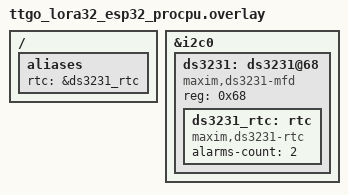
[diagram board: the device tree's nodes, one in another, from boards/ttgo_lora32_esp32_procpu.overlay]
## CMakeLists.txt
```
# SPDX-FileCopyrightText: 2026 Henrique Freire <hfreire10@hotmail.com>

# SPDX-License-Identifier: MIT

cmake_minimum_required(VERSION 3.20.0)

list(APPEND EXTRA_ZEPHYR_MODULES ${CMAKE_CURRENT_LIST_DIR}/../../modules/wifi_sensing)

find_package(Zephyr REQUIRED HINTS $ENV{ZEPHYR_BASE})
project(relay)

target_sources(app PRIVATE
  src/lora.c
  src/main.c
  src/storage.c
  src/time.c
  src/wifi.c
)
target_include_directories(app PRIVATE include)
```

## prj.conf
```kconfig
# SPDX-FileCopyrightText: 2026 Henrique Freire <hfreire10@hotmail.com>

# SPDX-License-Identifier: MIT

# Debug
CONFIG_LOG=y
CONFIG_THREAD_NAME=y
CONFIG_STACK_CANARIES=y
CONFIG_STACK_SENTINEL=y

# General
CONFIG_SPI=y
CONFIG_GPIO=y
CONFIG_FLASH=y
CONFIG_EVENTS=y
CONFIG_FLASH_MAP=y
CONFIG_STREAM_FLASH=y
CONFIG_LOG_DEFAULT_LEVEL=3
CONFIG_IDLE_STACK_SIZE=256
CONFIG_MAIN_STACK_SIZE=2048
CONFIG_HEAP_MEM_POOL_SIZE=102400
CONFIG_SYSTEM_WORKQUEUE_STACK_SIZE=1548

# RTC
CONFIG_I2C=y
CONFIG_RTC=y

# Bootloader
# CONFIG_IMG_MANAGER=y
# CONFIG_MCUBOOT_IMG_MANAGER=y

# Networking
CONFIG_NET_UDP=y
CONFIG_NET_IPV4=y
CONFIG_POSIX_API=y
CONFIG_NETWORKING=y
CONFIG_NET_SOCKETS=y
CONFIG_NET_TX_STACK_SIZE=4096
CONFIG_NET_RX_STACK_SIZE=4096
CONFIG_NET_SOCKETS_SERVICE_STACK_SIZE=3596

## LoRa
CONFIG_LORA=y

## DHCP
CONFIG_NET_DHCPV4_SERVER=y
CONFIG_NET_DHCPV4_SERVER_ADDR_COUNT=8
CONFIG_NET_CONFIG_SETTINGS=y
CONFIG_NET_CONFIG_AUTO_INIT=y
CONFIG_NET_CONFIG_MY_IPV4_GW="192.168.5.1"
CONFIG_NET_CONFIG_MY_IPV4_ADDR="192.168.5.1"
CONFIG_NET_CONFIG_MY_IPV4_NETMASK="255.255.255.0"

## WiFi
CONFIG_WIFI=y
CONFIG_WIFI_ESP32=y
CONFIG_NET_L2_WIFI_MGMT=y
CONFIG_ESP32_WIFI_IRAM_OPT=y
CONFIG_ESP32_WIFI_RX_IRAM_OPT=y
CONFIG_ESP32_WIFI_DYNAMIC_RX_BUFFER_NUM=48
#default value in seconds
CONFIG_WIFI_MGMT_AP_STA_INACTIVITY_TIMEOUT=300

# SD Card
CONFIG_DISK_ACCESS=y
CONFIG_FILE_SYSTEM=y
CONFIG_FS_FATFS_LFN=y
CONFIG_FAT_FILESYSTEM_ELM=y
```

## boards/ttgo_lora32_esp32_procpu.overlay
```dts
&i2c0 {
    status = "okay";

    ds3231: ds3231@68 {
        compatible = "maxim,ds3231-mfd";
        reg = <0x68>;
        status = "okay";

        ds3231_rtc: rtc {
            compatible = "maxim,ds3231-rtc";
            alarms-count = <2>;
            status = "okay";
        };
    };
};

/ {
    aliases {
        rtc = &ds3231_rtc;
    };
};
```

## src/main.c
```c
// SPDX-FileCopyrightText: 2026 Henrique Freire <hfreire10@hotmail.com>

// SPDX-License-Identifier: MIT

#include <zephyr/device.h>
#include <zephyr/kernel.h>
#include <zephyr/logging/log.h>
#include <zephyr/net/wifi_mgmt.h>

#include "lora.h"

#include "relay.h"

#define NET_EVENTS                                                                                 \
  (NET_EVENT_WIFI_AP_ENABLE_RESULT | NET_EVENT_WIFI_AP_STA_CONNECTED |                             \
   NET_EVENT_WIFI_AP_STA_DISCONNECTED)

LOG_MODULE_REGISTER(relay);

const struct device *g_lora_dev = DEVICE_DT_GET(LORA_NODE);

static struct net_mgmt_event_callback s_net_cb;

K_EVENT_DEFINE(g_ap_events);

K_FIFO_DEFINE(g_lora_fifo);
K_FIFO_DEFINE(g_storage_fifo);
K_MEM_SLAB_DEFINE_TYPE(g_csi_slab, csi_item_t, (MAX_MSGS / MAX_MSG_PAYLOAD));

static void net_event_handler(struct net_mgmt_event_callback *cb, uint64_t mgmt_event,
                              struct net_if *iface) {
  switch (mgmt_event) {
  case NET_EVENT_WIFI_AP_ENABLE_RESULT: {
    k_event_post(&g_ap_events, NET_READY);
    LOG_INF("AP Mode is enabled. Waiting for station to connect");
    break;
  }
  case NET_EVENT_WIFI_AP_STA_CONNECTED: {
    LOG_INF("Station connected");
    break;
  }
  case NET_EVENT_WIFI_AP_STA_DISCONNECTED: {
    LOG_INF("Station disconnected");
    break;
  }
  }
}

int main(void) {
  LOG_INF("Starting LoRa <-> Wi-Fi gateway");

  rtc_sync();

  net_mgmt_init_event_callback(&s_net_cb, net_event_handler, NET_EVENTS);
  net_mgmt_add_event_callback(&s_net_cb);

  sd_card_init();
  ap_init();
  lora_init(g_lora_dev, true);

  return 0;
}
```

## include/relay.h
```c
// SPDX-FileCopyrightText: 2026 Henrique Freire <hfreire10@hotmail.com>
//
// SPDX-License-Identifier: MIT

#pragma once

#include <inttypes.h>

#include <zephyr/kernel.h>
#include <zephyr/sys/atomic.h>

#include <wifi_sensing.h>

#define LORA_NODE DT_ALIAS(lora0)

typedef struct {
  void *fifo_reserved;
  atomic_t refs;
  uint8_t data[MSG_HDR_SIZE + MAX_MSG_PAYLOAD * CSI_DATA_SIZE];
} csi_item_t;

extern const struct device *g_lora_dev;
extern const struct device *g_rtc_dev;

extern struct k_event g_ap_events;
extern struct k_fifo g_lora_fifo;
extern struct k_fifo g_storage_fifo;
extern struct k_mem_slab g_csi_slab;

void ap_init(void);
void sd_card_init(void);
int rtc_sync(void);
uint64_t get_timestamp();
int get_current_utc(char *buf, size_t buf_size);
```

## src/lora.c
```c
// SPDX-FileCopyrightText: 2026 Henrique Freire <hfreire10@hotmail.com>

// SPDX-License-Identifier: MIT

#include <inttypes.h>

#include <zephyr/drivers/lora.h>
#include <zephyr/kernel.h>
#include <zephyr/logging/log.h>

#include <lora.h>
#include <wifi_sensing.h>

#include "relay.h"

#define LORA_TX_PRIORITY   4
#define LORA_TX_STACK_SIZE 1024

BUILD_ASSERT(DT_NODE_HAS_STATUS_OKAY(LORA_NODE), "No default LoRa radio specified in DT");

LOG_MODULE_DECLARE(relay);

static void lora_tx_thread(void *p1, void *p2, void *p3);

K_THREAD_DEFINE(lora_tx_tid, LORA_TX_STACK_SIZE, lora_tx_thread, NULL, NULL, NULL, LORA_TX_PRIORITY,
                0, 0);

static void lora_tx_thread(void *p1 __unused, void *p2 __unused, void *p3 __unused) {
  csi_item_t *item;

  lora_data_t data = {
      .hdr =
          {
              .magic = LORA_MAGIC,
              .id    = LORA_DATA_ID,
          },
  };

  while (true) {
    item = (csi_item_t *)k_fifo_get(&g_lora_fifo, K_FOREVER);

    const msg_t *const msg = (msg_t *)item->data;

    switch (msg->hdr.id) {
    case MSG_ID_SENSORS: {
      const sensor_data_t *const pkt = (sensor_data_t *)&msg->payload.sensor;

      memcpy((uint8_t *)&data.payload.sensor, (uint8_t *)pkt, SENSOR_DATA_SIZE);
      data.hdr.type      = MSG_ID_SENSORS;
      data.timestamp_sec = get_timestamp();

      int ret = lora_send(g_lora_dev, (uint8_t *)&data, LORA_HDR_SIZE + SENSOR_DATA_SIZE);
      if (ret < 0) {
        LOG_ERR("LoRa sensor send failed");
      }
      break;
    }
    case MSG_ID_CSI: {
      const csi_data_t *const pkt = (csi_data_t *)&msg->payload.csi;
      for (size_t i = 0; i < pkt->count; i++) {
        memcpy((uint8_t *)&data.payload.csi, (uint8_t *)&pkt->data[i], CSI_DATA_SIZE);
        data.hdr.type      = MSG_ID_CSI;
        data.timestamp_sec = get_timestamp();

        int ret = lora_send(g_lora_dev, (uint8_t *)&data, LORA_HDR_SIZE + CSI_DATA_SIZE);
        if (ret < 0) {
          LOG_ERR("LoRa CSI send failed");
        } else {
          LOG_INF("LoRa CSI sent");
        }
      }
      break;
    }
    default: {
      LOG_WRN("Unrecognized message received");
      break;
    }
    }

    if (atomic_dec(&item->refs) == 1) {
      k_mem_slab_free(&g_csi_slab, (void *)item);
    }
  }
}
```

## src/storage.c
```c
// SPDX-FileCopyrightText: 2026 Henrique Freire <hfreire10@hotmail.com>
//
// SPDX-License-Identifier: MIT

#include <zephyr/kernel.h>
#include <zephyr/logging/log.h>
#include <zephyr/storage/disk_access.h>

#include <ff.h>

#include <wifi_sensing.h>

#include "relay.h"

#define STORAGE_PRIORITY   5
#define STORAGE_STACK_SIZE 1024

#define DISK_DRIVE_NAME "SD"
#define DISK_MOUNT_PT   "/" DISK_DRIVE_NAME ":"

typedef struct {
  bool is_open;
  uint32_t key;
  struct fs_file_t file;
} file_node_t;

LOG_MODULE_DECLARE(relay);

static FATFS s_fat_fs;
static struct fs_mount_t s_mp = {
    .type      = FS_FATFS,
    .fs_data   = &s_fat_fs,
    .mnt_point = DISK_MOUNT_PT,
};

static void storage_thread(void *p1, void *p2, void *p3);

K_THREAD_DEFINE(storage_tid, STORAGE_STACK_SIZE, storage_thread, NULL, NULL, NULL, STORAGE_PRIORITY,
                0, 0);

void sd_card_init(void) {
  static const char *disk_pdrv = DISK_DRIVE_NAME;

  if (disk_access_ioctl(disk_pdrv, DISK_IOCTL_CTRL_INIT, NULL)) {
    LOG_ERR("Failed to init " DISK_DRIVE_NAME);
    return;
  }

  if (fs_mount(&s_mp)) {
    LOG_ERR(DISK_DRIVE_NAME " mount failed");
    return;
  }

  LOG_INF(DISK_DRIVE_NAME " mounted successfully");
}

static void storage_thread(void *p1 __unused, void *p2 __unused, void *p3 __unused) {
  csi_item_t *pkt;
  // Lower half corresponds to CSI files, while the upper half corresponds to reference sensors
  file_node_t open_files[2 * MAX_DEVICES] = {};

  while (true) {
    void *write_data;
    size_t write_size, start_idx, end_idx;
    const uint8_t (*mac_addr)[MAC_ADDR_LEN];

    pkt = k_fifo_get(&g_storage_fifo, K_FOREVER);

    const msg_t *const msg = (const msg_t *)pkt->data;
    switch (msg->hdr.id) {
    case MSG_ID_CSI: {
      start_idx  = 0;
      end_idx    = MAX_DEVICES;
      write_data = (void *)msg->payload.csi.data;
      write_size = msg->payload.csi.count * CSI_DATA_SIZE;
      mac_addr   = &msg->payload.csi.data[0].mac;
      break;
    }
    case MSG_ID_SENSORS: {
      start_idx  = MAX_DEVICES;
      end_idx    = 2 * MAX_DEVICES;
      write_data = (void *)&msg->payload.sensor;
      write_size = SENSOR_DATA_SIZE;
      mac_addr   = &msg->payload.sensor.mac;
      break;
    }
    default: {
      LOG_WRN("Unexpected message type");
      continue;
    }
    }

    uint32_t dev_key =
        (*mac_addr[2] << 24) | (*mac_addr[3] << 16) | (*mac_addr[4] << 8) | *mac_addr[5];

    int8_t free_idx   = -1;
    int8_t target_idx = -1;

    /* Search for an open file */
    for (size_t i = start_idx; i < end_idx; i++) {
      if (open_files[i].is_open && open_files[i].key == dev_key) {
        target_idx = i;
        break;
      }
      if (!open_files[i].is_open && free_idx == -1) {
        free_idx = i;
      }
    }

    /* Create new file (none open for the given device) */
    if (target_idx == -1 && free_idx != -1) {
      char file_path[40];

      /*
       * Filename for MAC address 01:23:45:67:89
       *
       * CSI    file: 01-23-45-67-89_csi.bin
       * Sensor file: 01-23-45-67-89_sensor.bin
       *
       */
      snprintf(file_path, sizeof(file_path),
               DISK_MOUNT_PT "/" MACSTR "%s"
                             ".bin",
               MAC2STR(*mac_addr), free_idx < MAX_DEVICES ? "_csi" : "_sensor");

      fs_file_t_init(&open_files[free_idx].file);

      if (fs_open(&open_files[free_idx].file, file_path, FS_O_CREATE | FS_O_APPEND | FS_O_WRITE) ==
          0) {
        target_idx                   = free_idx;
        open_files[free_idx].key     = dev_key;
        open_files[free_idx].is_open = true;

        LOG_INF("Opened new file stream for " MACSTR " at index %d", MAC2STR(*mac_addr),
                target_idx);
      } else {
        LOG_ERR("Failed to open file: %s", file_path);
        continue;
      }
    } else {
      LOG_ERR("Max devices reached. Cannot open new file");
      continue;
    }

    uint64_t time = get_timestamp();

    fs_write(&open_files[target_idx].file, &time, sizeof(time));
    fs_write(&open_files[target_idx].file, write_data, write_size);
    fs_sync(&open_files[target_idx].file);

    if (atomic_dec(&pkt->refs) == 1) {
      k_mem_slab_free(&g_csi_slab, (void *)pkt);
    }
  }
}
```

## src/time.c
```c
// SPDX-FileCopyrightText: 2026 Henrique Freire <hfreire10@hotmail.com>
//
// SPDX-License-Identifier: MIT

#include <errno.h>
#include <time.h>

#include <zephyr/device.h>
#include <zephyr/drivers/rtc.h>
#include <zephyr/kernel.h>
#include <zephyr/logging/log.h>
#include <zephyr/sys/clock.h>
#include <zephyr/sys/timeutil.h>

#include "relay.h"

#define RTC_SYNC_INTERVAL K_HOURS(24)

LOG_MODULE_DECLARE(relay);

static const struct device *s_rtc_dev = DEVICE_DT_GET(DT_ALIAS(rtc));

static int current_utc(struct tm *utc);
static int rtc_sync_system_time(void);
static void rtc_sync_work_handler(struct k_work *work);

K_WORK_DELAYABLE_DEFINE(rtc_sync_work, rtc_sync_work_handler);

int rtc_sync(void) {
  int ret = rtc_sync_system_time();

  if (ret < 0) {
    LOG_ERR("Initial RTC synchronization failed: %d", ret);
    return ret;
  }

  return k_work_reschedule(&rtc_sync_work, RTC_SYNC_INTERVAL);
}

uint64_t get_timestamp() {
  struct timespec ts;

  if (sys_clock_gettime(SYS_CLOCK_REALTIME, &ts) < 0) {
    return 0;
  } else {
    return (uint64_t)ts.tv_sec;
  }
}

int get_current_utc(char *buf, size_t buf_size) {
  int ret;
  struct tm utc;

  // YYYY-MM-DDThh:mm:ss => at least 20 bytes (with null terminator)
  if (!buf || buf_size < 20) {
    return -EINVAL;
  }

  ret = current_utc(&utc);
  if (ret < 0) {
    return ret;
  }

  return snprintf(buf, buf_size, "%04d-%02d-%02dT%02d:%02d:%02d", utc.tm_year + 1900,
                  utc.tm_mon + 1, utc.tm_mday, utc.tm_hour, utc.tm_min, utc.tm_sec);
}

static int current_utc(struct tm *utc) {
  struct timespec now;

  if (!utc) {
    return -EINVAL;
  }

  int ret = sys_clock_gettime(SYS_CLOCK_REALTIME, &now);
  if (ret < 0) {
    return ret;
  }

  if (gmtime_r(&now.tv_sec, utc) == NULL) {
    return -EOVERFLOW;
  }

  return 0;
}

static int rtc_sync_system_time(void) {
  int ret;
  time_t epoch;
  struct tm *tm;
  struct timespec ts;
  struct rtc_time rtc_time;

  if (!device_is_ready(s_rtc_dev)) {
    return -ENODEV;
  }

  ret = rtc_get_time(s_rtc_dev, &rtc_time);

  if (ret < 0) {
    return ret;
  }

  /* DS3231 stores years from 2000 through 2099.
   * struct rtc_time.tm_year is years since 1900
   */
  if (rtc_time.tm_year < 100 || rtc_time.tm_year > 199) {
    return -EINVAL;
  }

  tm    = rtc_time_to_tm(&rtc_time);
  epoch = timeutil_timegm(tm);

  if (epoch == (time_t)-1) {
    return -ERANGE;
  }

  ts.tv_sec  = epoch;
  ts.tv_nsec = 0; // DS3231 has one-second time resolution

  return sys_clock_settime(SYS_CLOCK_REALTIME, &ts);
}

static void rtc_sync_work_handler(struct k_work *work) {
  int ret = rtc_sync_system_time();

  if (ret < 0) {
    LOG_WRN("RTC synchronization failed: %d", ret);
  }

  // Schedule the next synchronization
  (void)k_work_reschedule(&rtc_sync_work, RTC_SYNC_INTERVAL);
}
```

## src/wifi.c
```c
// SPDX-FileCopyrightText: 2026 Henrique Freire <hfreire10@hotmail.com>

// SPDX-License-Identifier: MIT

#define WIFI_PRIORITY    3
#define PROBE_PRIORITY   3
#define WIFI_STACK_SIZE  1024
#define PROBE_STACK_SIZE 1024

#include <zephyr/device.h>
#include <zephyr/kernel.h>
#include <zephyr/logging/log.h>
#include <zephyr/net/dhcpv4_server.h>
#include <zephyr/net/socket.h>
#include <zephyr/net/wifi_mgmt.h>
#include <zephyr/posix/sys/socket.h>
#include <zephyr/posix/unistd.h>
#include <zephyr/sys/atomic.h>

#include <esp_err.h>
#include <esp_wifi.h>

#include <wifi_sensing.h>

#include "relay.h"

#define WIFI_RX_PRIORITY   3
#define WIFI_TX_PRIORITY   3
#define WIFI_RX_STACK_SIZE 1024
#define WIFI_TX_STACK_SIZE 1024

BUILD_ASSERT(sizeof(CONFIG_WIFI_SSID) > 1,
             "CONFIG_WIFI_SSID is empty. Please set it in conf file.");

BUILD_ASSERT(sizeof(CONFIG_WIFI_SSID) <= 32,
             "CONFIG_WIFI_SSID is too long (> 32). Please shorten it in conf file.");

BUILD_ASSERT(sizeof(CONFIG_WIFI_PSK) > 1, "CONFIG_WIFI_PSK is empty. Please set it in conf file.");

LOG_MODULE_DECLARE(relay);

static struct net_if *s_iface;

static void wifi_rx_thread(void *p1, void *p2, void *p3);
static void wifi_tx_thread(void *p1, void *p2, void *p3);

K_THREAD_DEFINE(wifi_rx_tid, WIFI_RX_STACK_SIZE, wifi_rx_thread, NULL, NULL, NULL, WIFI_RX_PRIORITY,
                0, 0);
K_THREAD_DEFINE(wifi_tx_tid, WIFI_TX_STACK_SIZE, wifi_tx_thread, NULL, NULL, NULL, WIFI_TX_PRIORITY,
                0, 0);

void ap_init(void) {
  s_iface = net_if_get_wifi_sap();

  /*wifi_tx_rate_config_t phy_config = {
    .phymode = WIFI_PHY_MODE_11G,
    .rate    = WIFI_PHY_RATE_6M,
  };*/

  if (esp_wifi_config_80211_tx_rate(WIFI_IF_AP, WIFI_PHY_RATE_6M) != ESP_OK) {
    LOG_ERR("Failed to set phy rate for probing frames");
    return;
  }

  struct wifi_connect_req_params ap_config = {
      .ssid        = CONFIG_WIFI_SSID,
      .ssid_length = strlen(CONFIG_WIFI_SSID),
      .psk         = CONFIG_WIFI_PSK,
      .psk_length  = strlen(CONFIG_WIFI_PSK),
      .channel     = CONFIG_WIFI_CHANNEL,
      .security    = WIFI_SECURITY_TYPE_PSK,
  };
  int ret = net_mgmt(NET_REQUEST_WIFI_AP_ENABLE, s_iface, &ap_config, sizeof(ap_config));
  if (ret) {
    LOG_ERR("NET_REQUEST_WIFI_AP_ENABLE failed, err: %d", ret);
    return;
  }

  struct in_addr pool_start;
  net_addr_pton(AF_INET, "192.168.5.2", &pool_start);

  if (net_dhcpv4_server_start(s_iface, &pool_start) < 0) {
    LOG_ERR("Failed to start DHCP server");
  } else {
    LOG_INF("DHCP server started successfully");
  }
}

static void wifi_rx_thread(void *p1 __unused, void *p2 __unused, void *p3 __unused) {
  int sock;

  struct sockaddr_in bind_addr = {
      .sin_family      = AF_INET,
      .sin_port        = htons(CONFIG_UDP_PORT),
      .sin_addr.s_addr = htonl(INADDR_ANY),
  };

  sock = socket(AF_INET, SOCK_DGRAM, IPPROTO_UDP);
  if (sock < 0) {
    LOG_ERR("Failed to create UDP socket");
    return;
  }

  if (bind(sock, (struct sockaddr *)&bind_addr, sizeof(bind_addr)) < 0) {
    LOG_ERR("Failed to bind UDP socket");
    return;
  }

  LOG_INF("UDP server listening on port %d", CONFIG_UDP_PORT);

  while (true) {
    struct sockaddr_in client_addr;
    socklen_t client_addr_len = sizeof(client_addr);

    // Allocate shared memory slab for received CSI data
    csi_item_t *item;
    k_mem_slab_alloc(&g_csi_slab, (void **)&item, K_FOREVER);

    ssize_t len = recvfrom(sock, item->data, sizeof(item->data), 0, (struct sockaddr *)&client_addr,
                           &client_addr_len);

    if (len < 0) {
      LOG_ERR("Wi-Fi recv failed (%zd)", len);
      k_mem_slab_free(&g_csi_slab, (void *)item);
      continue;
    }

    const uint16_t id = ((msg_t *)item->data)->hdr.id;
    if (id != MSG_ID_CSI && id != MSG_ID_SENSORS) {
      LOG_WRN("Unexpected message type");
      k_mem_slab_free(&g_csi_slab, (void *)item);
      continue;
    }

    LOG_INF("Received %zd bytes from STA", len);
    LOG_HEXDUMP_INF(((msg_t *)item->data)->payload.csi.data, CSI_DATA_SIZE, "CSI data: ");

    // Send shared allocated memory to both storage and lora threads (reference counting)
    atomic_set(&item->refs, 2);

    k_fifo_put(&g_storage_fifo, item);
    k_fifo_put(&g_lora_fifo, item);
  }
}

static void wifi_tx_thread(void *p1 __unused, void *p2 __unused, void *p3 __unused) {
  static uint8_t msg[sizeof(wifi_action_frame_t) + MSG_HDR_SIZE + PROBE_DATA_SIZE];

  k_event_wait(&g_ap_events, NET_READY, false, K_FOREVER);
  const struct net_linkaddr *link_addr = net_if_get_link_addr(s_iface);

  wifi_action_frame_t *const frame = (wifi_action_frame_t *)&msg;

  *frame = (wifi_action_frame_t){
      .frame_ctrl.subtype = ACTION_FRAME_SUBTYPE, // Action frame
      .category           = 127,                  // Vendor Specific
      .action             = 1,                    // Arbitrary Action Detail
  };
  memcpy(frame->da, g_broadcast_addr, MAC_ADDR_LEN);
  memcpy(frame->sa, link_addr->addr, MAC_ADDR_LEN);
  memcpy(frame->bss, link_addr->addr, MAC_ADDR_LEN);

  msg_hdr_t *const hdr = (msg_hdr_t *)frame->body;
  hdr->id              = MSG_ID_PROBE;

  probe_data_t *const probe = (probe_data_t *)&((msg_t *)frame->body)->payload.probe;

  while (true) {
    int64_t next_wake_time = k_uptime_get();

    for (size_t i = 0; i < SENSING_WINDOW_SIZE; i++) {
      next_wake_time += SENSING_PERIOD_MSEC;

      esp_err_t ret = esp_wifi_80211_tx(WIFI_IF_AP, msg, sizeof(msg), true);

      if (ret != ESP_OK) {
        LOG_ERR("Failed to send probe frame: %d", ret);
      } else {
        LOG_INF("Probe frame sent");
      }

      // Advance sequence for next measerument request
      probe->seq++;
      k_sleep(K_TIMEOUT_ABS_MS(next_wake_time));
    }

    k_sleep(K_MSEC(1000 * SENSING_INTERVAL_SEC - SENSING_WINDOW_SIZE * SENSING_PERIOD_MSEC));
  }
}
```
